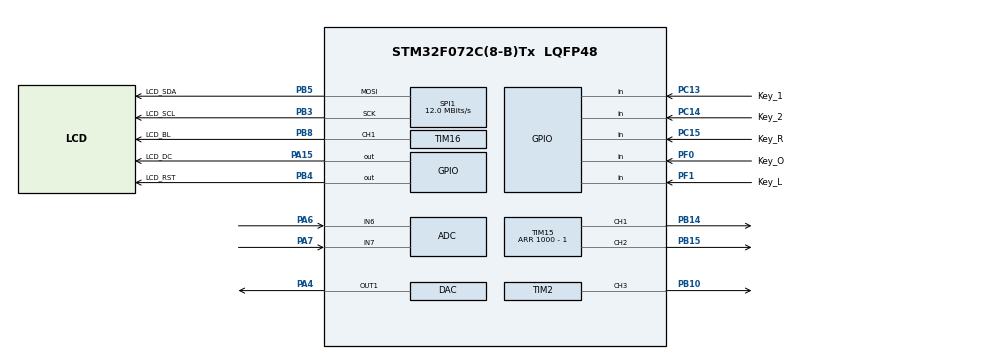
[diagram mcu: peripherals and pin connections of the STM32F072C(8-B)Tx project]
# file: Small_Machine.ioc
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ADC.DMAContinuousRequests=ENABLE
ADC.ExternalTrigConv=ADC_EXTERNALTRIGCONV_T1_TRGO
DAC.DAC_Trigger=DAC_TRIGGER_T3_TRGO
Dma.ADC.0.Direction=DMA_PERIPH_TO_MEMORY
Dma.ADC.0.Instance=DMA1_Channel1
Dma.ADC.0.MemDataAlignment=DMA_MDATAALIGN_HALFWORD
Dma.ADC.0.MemInc=DMA_MINC_ENABLE
Dma.ADC.0.Mode=DMA_CIRCULAR
Dma.ADC.0.PeriphDataAlignment=DMA_PDATAALIGN_HALFWORD
Dma.ADC.0.PeriphInc=DMA_PINC_DISABLE
Dma.ADC.0.Priority=DMA_PRIORITY_HIGH
Dma.DAC_CH1.1.Direction=DMA_MEMORY_TO_PERIPH
Dma.DAC_CH1.1.Instance=DMA1_Channel3
Dma.DAC_CH1.1.MemDataAlignment=DMA_MDATAALIGN_HALFWORD
Dma.DAC_CH1.1.MemInc=DMA_MINC_ENABLE
Dma.DAC_CH1.1.Mode=DMA_CIRCULAR
Dma.DAC_CH1.1.PeriphDataAlignment=DMA_PDATAALIGN_HALFWORD
Dma.DAC_CH1.1.PeriphInc=DMA_PINC_DISABLE
Dma.DAC_CH1.1.Priority=DMA_PRIORITY_MEDIUM
Dma.Request0=ADC
Dma.Request1=DAC_CH1
Mcu.Family=STM32F0
Mcu.Name=STM32F072C(8-B)Tx
Mcu.Package=LQFP48
NVIC.DMA1_Channel1_IRQn=true\:0\:0\:false\:false\:true\:false\:true
NVIC.DMA1_Channel2_3_IRQn=true\:0\:0\:false\:false\:true\:false\:true
NVIC.TIM1_BRK_UP_TRG_COM_IRQn=true\:0\:0\:false\:false\:true\:true\:true
NVIC.TIM7_IRQn=true\:1\:0\:true\:false\:true\:true\:true
PA13.Mode=Serial_Wire
PA13.Signal=SYS_SWDIO
PA14.Mode=Serial_Wire
PA14.Signal=SYS_SWCLK
PA15.GPIO_Label=LCD_DC
PA15.GPIO_Speed=GPIO_SPEED_FREQ_HIGH
PA15.Signal=GPIO_Output
PA4.Signal=COMP_DAC1_group
PA6.Mode=IN6
PA6.Signal=ADC_IN6
PA7.Mode=IN7
PA7.Signal=ADC_IN7
PB10.Signal=S_TIM2_CH3
PB14.Signal=S_TIM15_CH1
PB15.Signal=S_TIM15_CH2
PB3.GPIO_Label=LCD_SCL
PB3.Mode=TX_Only_Simplex_Unidirect_Master
PB3.Signal=SPI1_SCK
PB4.GPIO_Label=LCD_RST
PB4.GPIO_Speed=GPIO_SPEED_FREQ_HIGH
PB4.Signal=GPIO_Output
PB5.GPIO_Label=LCD_SDA
PB5.Mode=TX_Only_Simplex_Unidirect_Master
PB5.Signal=SPI1_MOSI
PB8.GPIO_Label=LCD_BL
PB8.Signal=S_TIM16_CH1
PC13.GPIO_Label=Key_1
PC13.GPIO_PuPd=GPIO_PULLDOWN
PC13.Signal=GPIO_Input
PC14-OSC32_IN.GPIO_Label=Key_2
PC14-OSC32_IN.GPIO_PuPd=GPIO_PULLDOWN
PC14-OSC32_IN.Signal=GPIO_Input
PC15-OSC32_OUT.GPIO_Label=Key_R
PC15-OSC32_OUT.GPIO_PuPd=GPIO_PULLDOWN
PC15-OSC32_OUT.Signal=GPIO_Input
PF0-OSC_IN.GPIO_Label=Key_O
PF0-OSC_IN.GPIO_PuPd=GPIO_PULLDOWN
PF0-OSC_IN.Signal=GPIO_Input
PF1-OSC_OUT.GPIO_Label=Key_L
PF1-OSC_OUT.GPIO_PuPd=GPIO_PULLDOWN
PF1-OSC_OUT.Signal=GPIO_Input
ProjectManager.HeapSize=0x200
ProjectManager.StackSize=0x400
ProjectManager.TargetToolchain=STM32CubeIDE
RCC.AHBFreq_Value=48000000
RCC.APB1Freq_Value=48000000
RCC.APB1TimFreq_Value=48000000
RCC.HCLKFreq_Value=48000000
RCC.PLLMUL=RCC_PLL_MUL6
RCC.SYSCLKFreq_VALUE=48000000
RCC.SYSCLKSource=RCC_SYSCLKSOURCE_PLLCLK
SH.COMP_DAC1_group.0=DAC_OUT1,DAC_OUT1
SH.S_TIM15_CH1.0=TIM15_CH1,PWM Generation1 CH1
SH.S_TIM15_CH2.0=TIM15_CH2,PWM Generation2 CH2
SH.S_TIM16_CH1.0=TIM16_CH1,PWM Generation1 CH1
SH.S_TIM2_CH3.0=TIM2_CH3,PWM Generation3 CH3
SPI1.BaudRatePrescaler=SPI_BAUDRATEPRESCALER_4
SPI1.CLKPhase=SPI_PHASE_2EDGE
SPI1.CLKPolarity=SPI_POLARITY_HIGH
SPI1.CalculateBaudRate=12.0 MBits/s
SPI1.DataSize=SPI_DATASIZE_8BIT
SPI1.Direction=SPI_DIRECTION_2LINES
SPI1.Mode=SPI_MODE_MASTER
SPI1.VirtualType=VM_MASTER
TIM1.Period=1000 - 1
TIM1.Prescaler=48 - 1
TIM1.TIM_MasterOutputTrigger=TIM_TRGO_UPDATE
TIM15.Channel-PWM\ Generation1\ CH1=TIM_CHANNEL_1
TIM15.Channel-PWM\ Generation2\ CH2=TIM_CHANNEL_2
TIM15.Period=1000 - 1
TIM16.Channel=TIM_CHANNEL_1
TIM16.Period=10000 - 1
TIM16.Pulse=9999
TIM2.Channel-PWM\ Generation3\ CH3=TIM_CHANNEL_3
TIM2.Period=1000 - 1
TIM2.Prescaler=72 - 1
TIM3.AutoReloadPreload=TIM_AUTORELOAD_PRELOAD_ENABLE
TIM3.Period=72 - 1
TIM3.TIM_MasterOutputTrigger=TIM_TRGO_UPDATE
TIM7.AutoReloadPreload=TIM_AUTORELOAD_PRELOAD_DISABLE
TIM7.Period=1000 - 1
TIM7.Prescaler=72 - 1
VP_TIM15_VS_ClockSourceINT.Mode=Internal
VP_TIM16_VS_ClockSourceINT.Mode=Enable_Timer
VP_TIM1_VS_ClockSourceINT.Mode=Internal
VP_TIM2_VS_ClockSourceINT.Mode=Internal
VP_TIM3_VS_ClockSourceINT.Mode=Internal
VP_TIM7_VS_ClockSourceINT.Mode=Enable_Timer
board=custom

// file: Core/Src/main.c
/* USER CODE BEGIN Header */
/**
  ******************************************************************************
  * @file           : main.c
  * @brief          : Main program body
  ******************************************************************************
  * @attention
  *
  * <h2><center>&copy; Copyright (c) 2021 STMicroelectronics.
  * All rights reserved.</center></h2>
  *
  * This software component is licensed by ST under BSD 3-Clause license,
  * the "License"; You may not use this file except in compliance with the
  * License. You may obtain a copy of the License at:
  *                        opensource.org/licenses/BSD-3-Clause
  *
  ******************************************************************************
  */
/* USER CODE END Header */
#include "main.h"
#include "adc.h"
#include "dac.h"
#include "dma.h"
#include "spi.h"
#include "tim.h"
#include "gpio.h"

/* USER CODE BEGIN Includes */
#include "User.h"
/* USER CODE END Includes */

void SystemClock_Config(void);

int main(void)
{

  /* MCU Configuration--------------------------------------------------------*/

  /* Reset of all peripherals, Initializes the Flash interface and the Systick. */
  HAL_Init();

  /* Configure the system clock */
  SystemClock_Config();

  /* Initialize all configured peripherals */
  MX_GPIO_Init();
  MX_DMA_Init();
  MX_SPI1_Init();
  MX_TIM16_Init();
  MX_ADC_Init();
  MX_TIM1_Init();
  MX_DAC_Init();
  MX_TIM3_Init();
  MX_TIM7_Init();
  MX_TIM2_Init();
  MX_TIM15_Init();
  /* USER CODE BEGIN 2 */
	User_Init();

  /* USER CODE END 2 */

  /* Infinite loop */
  /* USER CODE BEGIN WHILE */
  while (1)
  {
		User_Loop();
    /* USER CODE END WHILE */

  }
}

void SystemClock_Config(void)
{
  RCC_OscInitTypeDef RCC_OscInitStruct = {0};
  RCC_ClkInitTypeDef RCC_ClkInitStruct = {0};

  /** Initializes the RCC Oscillators according to the specified parameters
  * in the RCC_OscInitTypeDef structure.
  */
  RCC_OscInitStruct.OscillatorType = RCC_OSCILLATORTYPE_HSI|RCC_OSCILLATORTYPE_HSI14;
  RCC_OscInitStruct.HSIState = RCC_HSI_ON;
  RCC_OscInitStruct.HSI14State = RCC_HSI14_ON;
  RCC_OscInitStruct.HSICalibrationValue = RCC_HSICALIBRATION_DEFAULT;
  RCC_OscInitStruct.HSI14CalibrationValue = 16;
  RCC_OscInitStruct.PLL.PLLState = RCC_PLL_ON;
  RCC_OscInitStruct.PLL.PLLSource = RCC_PLLSOURCE_HSI;
  RCC_OscInitStruct.PLL.PLLMUL = RCC_PLL_MUL9;
  RCC_OscInitStruct.PLL.PREDIV = RCC_PREDIV_DIV1;
  if (HAL_RCC_OscConfig(&RCC_OscInitStruct) != HAL_OK)
  {
    Error_Handler();
  }
  /** Initializes the CPU, AHB and APB buses clocks
  */
  RCC_ClkInitStruct.ClockType = RCC_CLOCKTYPE_HCLK|RCC_CLOCKTYPE_SYSCLK
                              |RCC_CLOCKTYPE_PCLK1;
  RCC_ClkInitStruct.SYSCLKSource = RCC_SYSCLKSOURCE_PLLCLK;
  RCC_ClkInitStruct.AHBCLKDivider = RCC_SYSCLK_DIV1;
  RCC_ClkInitStruct.APB1CLKDivider = RCC_HCLK_DIV1;

  if (HAL_RCC_ClockConfig(&RCC_ClkInitStruct, FLASH_LATENCY_1) != HAL_OK)
  {
    Error_Handler();
  }
}

void Error_Handler(void)
{
  __disable_irq();
  while (1)
  {
  }
}

/************************ (C) COPYRIGHT STMicroelectronics *****END OF FILE****/
